VERSION 5.7 ;
  NOWIREEXTENSIONATPIN ON ;
  DIVIDERCHAR "/" ;
  BUSBITCHARS "[]" ;
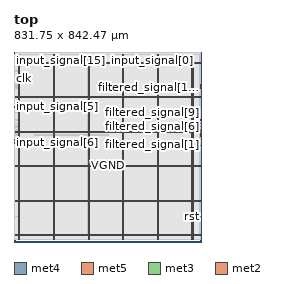
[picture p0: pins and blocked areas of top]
MACRO top
  CLASS BLOCK ;
  FOREIGN top ;
  ORIGIN 0.000 0.000 ;
  SIZE 831.750 BY 842.470 ;
  PIN VGND
    DIRECTION INOUT ;
    USE GROUND ;
    PORT
      LAYER met4 ;
        RECT 24.340 10.640 25.940 829.840 ;
    END
    PORT
      LAYER met4 ;
        RECT 177.940 10.640 179.540 829.840 ;
    END
    PORT
      LAYER met4 ;
        RECT 331.540 10.640 333.140 829.840 ;
    END
    PORT
      LAYER met4 ;
        RECT 485.140 10.640 486.740 829.840 ;
    END
    PORT
      LAYER met4 ;
        RECT 638.740 10.640 640.340 829.840 ;
    END
    PORT
      LAYER met4 ;
        RECT 792.340 10.640 793.940 829.840 ;
    END
    PORT
      LAYER met5 ;
        RECT 5.280 30.030 826.400 31.630 ;
    END
    PORT
      LAYER met5 ;
        RECT 5.280 183.210 826.400 184.810 ;
    END
    PORT
      LAYER met5 ;
        RECT 5.280 336.390 826.400 337.990 ;
    END
    PORT
      LAYER met5 ;
        RECT 5.280 489.570 826.400 491.170 ;
    END
    PORT
      LAYER met5 ;
        RECT 5.280 642.750 826.400 644.350 ;
    END
    PORT
      LAYER met5 ;
        RECT 5.280 795.930 826.400 797.530 ;
    END
  END VGND
  PIN VPWR
    DIRECTION INOUT ;
    USE POWER ;
    PORT
      LAYER met4 ;
        RECT 21.040 10.640 22.640 829.840 ;
    END
    PORT
      LAYER met4 ;
        RECT 174.640 10.640 176.240 829.840 ;
    END
    PORT
      LAYER met4 ;
        RECT 328.240 10.640 329.840 829.840 ;
    END
    PORT
      LAYER met4 ;
        RECT 481.840 10.640 483.440 829.840 ;
    END
    PORT
      LAYER met4 ;
        RECT 635.440 10.640 637.040 829.840 ;
    END
    PORT
      LAYER met4 ;
        RECT 789.040 10.640 790.640 829.840 ;
    END
    PORT
      LAYER met5 ;
        RECT 5.280 26.730 826.400 28.330 ;
    END
    PORT
      LAYER met5 ;
        RECT 5.280 179.910 826.400 181.510 ;
    END
    PORT
      LAYER met5 ;
        RECT 5.280 333.090 826.400 334.690 ;
    END
    PORT
      LAYER met5 ;
        RECT 5.280 486.270 826.400 487.870 ;
    END
    PORT
      LAYER met5 ;
        RECT 5.280 639.450 826.400 641.050 ;
    END
    PORT
      LAYER met5 ;
        RECT 5.280 792.630 826.400 794.230 ;
    END
  END VPWR
  PIN clk
    DIRECTION INPUT ;
    USE SIGNAL ;
    ANTENNAGATEAREA 0.852000 ;
    ANTENNADIFFAREA 0.434700 ;
    PORT
      LAYER met3 ;
        RECT 0.000 758.240 4.000 758.840 ;
    END
  END clk
  PIN filtered_signal[0]
    DIRECTION OUTPUT ;
    USE SIGNAL ;
    ANTENNADIFFAREA 0.445500 ;
    PORT
      LAYER met3 ;
        RECT 827.750 428.440 831.750 429.040 ;
    END
  END filtered_signal[0]
  PIN filtered_signal[10]
    DIRECTION OUTPUT ;
    USE SIGNAL ;
    ANTENNADIFFAREA 0.795200 ;
    PORT
      LAYER met3 ;
        RECT 827.750 697.040 831.750 697.640 ;
    END
  END filtered_signal[10]
  PIN filtered_signal[11]
    DIRECTION OUTPUT ;
    USE SIGNAL ;
    ANTENNADIFFAREA 0.445500 ;
    PORT
      LAYER met3 ;
        RECT 827.750 683.440 831.750 684.040 ;
    END
  END filtered_signal[11]
  PIN filtered_signal[12]
    DIRECTION OUTPUT ;
    USE SIGNAL ;
    ANTENNADIFFAREA 0.795200 ;
    PORT
      LAYER met3 ;
        RECT 827.750 690.240 831.750 690.840 ;
    END
  END filtered_signal[12]
  PIN filtered_signal[13]
    DIRECTION OUTPUT ;
    USE SIGNAL ;
    ANTENNADIFFAREA 0.445500 ;
    PORT
      LAYER met3 ;
        RECT 827.750 686.840 831.750 687.440 ;
    END
  END filtered_signal[13]
  PIN filtered_signal[14]
    DIRECTION OUTPUT ;
    USE SIGNAL ;
    ANTENNADIFFAREA 0.445500 ;
    PORT
      LAYER met3 ;
        RECT 827.750 680.040 831.750 680.640 ;
    END
  END filtered_signal[14]
  PIN filtered_signal[15]
    DIRECTION OUTPUT ;
    USE SIGNAL ;
    ANTENNADIFFAREA 0.795200 ;
    PORT
      LAYER met3 ;
        RECT 827.750 693.640 831.750 694.240 ;
    END
  END filtered_signal[15]
  PIN filtered_signal[1]
    DIRECTION OUTPUT ;
    USE SIGNAL ;
    ANTENNADIFFAREA 0.445500 ;
    PORT
      LAYER met3 ;
        RECT 827.750 469.240 831.750 469.840 ;
    END
  END filtered_signal[1]
  PIN filtered_signal[2]
    DIRECTION OUTPUT ;
    USE SIGNAL ;
    ANTENNADIFFAREA 0.445500 ;
    PORT
      LAYER met3 ;
        RECT 827.750 479.440 831.750 480.040 ;
    END
  END filtered_signal[2]
  PIN filtered_signal[3]
    DIRECTION OUTPUT ;
    USE SIGNAL ;
    ANTENNADIFFAREA 0.445500 ;
    PORT
      LAYER met3 ;
        RECT 827.750 476.040 831.750 476.640 ;
    END
  END filtered_signal[3]
  PIN filtered_signal[4]
    DIRECTION OUTPUT ;
    USE SIGNAL ;
    ANTENNADIFFAREA 0.445500 ;
    PORT
      LAYER met3 ;
        RECT 827.750 499.840 831.750 500.440 ;
    END
  END filtered_signal[4]
  PIN filtered_signal[5]
    DIRECTION OUTPUT ;
    USE SIGNAL ;
    ANTENNADIFFAREA 0.445500 ;
    PORT
      LAYER met3 ;
        RECT 827.750 493.040 831.750 493.640 ;
    END
  END filtered_signal[5]
  PIN filtered_signal[6]
    DIRECTION OUTPUT ;
    USE SIGNAL ;
    ANTENNADIFFAREA 0.445500 ;
    PORT
      LAYER met3 ;
        RECT 827.750 513.440 831.750 514.040 ;
    END
  END filtered_signal[6]
  PIN filtered_signal[7]
    DIRECTION OUTPUT ;
    USE SIGNAL ;
    ANTENNADIFFAREA 0.795200 ;
    PORT
      LAYER met3 ;
        RECT 827.750 510.040 831.750 510.640 ;
    END
  END filtered_signal[7]
  PIN filtered_signal[8]
    DIRECTION OUTPUT ;
    USE SIGNAL ;
    ANTENNADIFFAREA 0.795200 ;
    PORT
      LAYER met3 ;
        RECT 827.750 523.640 831.750 524.240 ;
    END
  END filtered_signal[8]
  PIN filtered_signal[9]
    DIRECTION OUTPUT ;
    USE SIGNAL ;
    ANTENNADIFFAREA 0.445500 ;
    PORT
      LAYER met3 ;
        RECT 827.750 540.640 831.750 541.240 ;
    END
  END filtered_signal[9]
  PIN input_signal[0]
    DIRECTION INPUT ;
    USE SIGNAL ;
    ANTENNAGATEAREA 0.213000 ;
    ANTENNADIFFAREA 0.434700 ;
    PORT
      LAYER met2 ;
        RECT 615.110 838.470 615.390 842.470 ;
    END
  END input_signal[0]
  PIN input_signal[10]
    DIRECTION INPUT ;
    USE SIGNAL ;
    ANTENNAGATEAREA 0.196500 ;
    ANTENNADIFFAREA 0.434700 ;
    PORT
      LAYER met3 ;
        RECT 0.000 455.640 4.000 456.240 ;
    END
  END input_signal[10]
  PIN input_signal[11]
    DIRECTION INPUT ;
    USE SIGNAL ;
    ANTENNAGATEAREA 0.196500 ;
    ANTENNADIFFAREA 0.434700 ;
    PORT
      LAYER met3 ;
        RECT 0.000 448.840 4.000 449.440 ;
    END
  END input_signal[11]
  PIN input_signal[12]
    DIRECTION INPUT ;
    USE SIGNAL ;
    ANTENNAGATEAREA 0.196500 ;
    ANTENNADIFFAREA 0.434700 ;
    PORT
      LAYER met3 ;
        RECT 0.000 428.440 4.000 429.040 ;
    END
  END input_signal[12]
  PIN input_signal[13]
    DIRECTION INPUT ;
    USE SIGNAL ;
    ANTENNAGATEAREA 0.196500 ;
    ANTENNADIFFAREA 0.434700 ;
    PORT
      LAYER met3 ;
        RECT 0.000 431.840 4.000 432.440 ;
    END
  END input_signal[13]
  PIN input_signal[14]
    DIRECTION INPUT ;
    USE SIGNAL ;
    ANTENNAGATEAREA 0.196500 ;
    ANTENNADIFFAREA 0.434700 ;
    PORT
      LAYER met3 ;
        RECT 0.000 452.240 4.000 452.840 ;
    END
  END input_signal[14]
  PIN input_signal[15]
    DIRECTION INPUT ;
    USE SIGNAL ;
    ANTENNAGATEAREA 0.196500 ;
    ANTENNADIFFAREA 0.434700 ;
    PORT
      LAYER met2 ;
        RECT 83.810 838.470 84.090 842.470 ;
    END
  END input_signal[15]
  PIN input_signal[1]
    DIRECTION INPUT ;
    USE SIGNAL ;
    ANTENNAGATEAREA 0.159000 ;
    ANTENNADIFFAREA 0.434700 ;
    PORT
      LAYER met2 ;
        RECT 599.010 838.470 599.290 842.470 ;
    END
  END input_signal[1]
  PIN input_signal[2]
    DIRECTION INPUT ;
    USE SIGNAL ;
    ANTENNAGATEAREA 0.159000 ;
    ANTENNADIFFAREA 0.434700 ;
    PORT
      LAYER met2 ;
        RECT 576.470 838.470 576.750 842.470 ;
    END
  END input_signal[2]
  PIN input_signal[3]
    DIRECTION INPUT ;
    USE SIGNAL ;
    ANTENNAGATEAREA 0.196500 ;
    ANTENNADIFFAREA 0.434700 ;
    PORT
      LAYER met3 ;
        RECT 0.000 574.640 4.000 575.240 ;
    END
  END input_signal[3]
  PIN input_signal[4]
    DIRECTION INPUT ;
    USE SIGNAL ;
    ANTENNAGATEAREA 0.196500 ;
    ANTENNADIFFAREA 0.434700 ;
    PORT
      LAYER met3 ;
        RECT 0.000 595.040 4.000 595.640 ;
    END
  END input_signal[4]
  PIN input_signal[5]
    DIRECTION INPUT ;
    USE SIGNAL ;
    ANTENNAGATEAREA 0.196500 ;
    ANTENNADIFFAREA 0.434700 ;
    PORT
      LAYER met3 ;
        RECT 0.000 598.440 4.000 599.040 ;
    END
  END input_signal[5]
  PIN input_signal[6]
    DIRECTION INPUT ;
    USE SIGNAL ;
    ANTENNAGATEAREA 0.196500 ;
    ANTENNADIFFAREA 0.434700 ;
    PORT
      LAYER met3 ;
        RECT 0.000 442.040 4.000 442.640 ;
    END
  END input_signal[6]
  PIN input_signal[7]
    DIRECTION INPUT ;
    USE SIGNAL ;
    ANTENNAGATEAREA 0.196500 ;
    ANTENNADIFFAREA 0.434700 ;
    PORT
      LAYER met3 ;
        RECT 0.000 435.240 4.000 435.840 ;
    END
  END input_signal[7]
  PIN input_signal[8]
    DIRECTION INPUT ;
    USE SIGNAL ;
    ANTENNAGATEAREA 0.196500 ;
    ANTENNADIFFAREA 0.434700 ;
    PORT
      LAYER met3 ;
        RECT 0.000 445.440 4.000 446.040 ;
    END
  END input_signal[8]
  PIN input_signal[9]
    DIRECTION INPUT ;
    USE SIGNAL ;
    ANTENNAGATEAREA 0.196500 ;
    ANTENNADIFFAREA 0.434700 ;
    PORT
      LAYER met3 ;
        RECT 0.000 438.640 4.000 439.240 ;
    END
  END input_signal[9]
  PIN rst
    DIRECTION INPUT ;
    USE SIGNAL ;
    ANTENNAGATEAREA 0.213000 ;
    ANTENNADIFFAREA 0.434700 ;
    PORT
      LAYER met3 ;
        RECT 827.750 112.240 831.750 112.840 ;
    END
  END rst
  PIN tap[0]
    DIRECTION INPUT ;
    USE SIGNAL ;
    ANTENNAGATEAREA 0.247500 ;
    ANTENNADIFFAREA 0.434700 ;
    PORT
      LAYER met2 ;
        RECT 634.430 838.470 634.710 842.470 ;
    END
  END tap[0]
  PIN tap[1]
    DIRECTION INPUT ;
    USE SIGNAL ;
    ANTENNAGATEAREA 0.213000 ;
    ANTENNADIFFAREA 0.434700 ;
    PORT
      LAYER met2 ;
        RECT 631.210 838.470 631.490 842.470 ;
    END
  END tap[1]
  PIN tap[2]
    DIRECTION INPUT ;
    USE SIGNAL ;
    ANTENNAGATEAREA 0.247500 ;
    ANTENNADIFFAREA 0.434700 ;
    PORT
      LAYER met3 ;
        RECT 827.750 465.840 831.750 466.440 ;
    END
  END tap[2]
  PIN tap[3]
    DIRECTION INPUT ;
    USE SIGNAL ;
    ANTENNAGATEAREA 0.247500 ;
    ANTENNADIFFAREA 0.434700 ;
    PORT
      LAYER met3 ;
        RECT 827.750 472.640 831.750 473.240 ;
    END
  END tap[3]
  OBS
      LAYER li1 ;
        RECT 5.520 10.795 826.160 829.685 ;
      LAYER met1 ;
        RECT 5.130 10.640 827.930 829.840 ;
      LAYER met2 ;
        RECT 5.150 838.190 83.530 838.470 ;
        RECT 84.370 838.190 576.190 838.470 ;
        RECT 577.030 838.190 598.730 838.470 ;
        RECT 599.570 838.190 614.830 838.470 ;
        RECT 615.670 838.190 630.930 838.470 ;
        RECT 631.770 838.190 634.150 838.470 ;
        RECT 634.990 838.190 827.900 838.470 ;
        RECT 5.150 10.695 827.900 838.190 ;
      LAYER met3 ;
        RECT 4.000 759.240 827.750 831.465 ;
        RECT 4.400 757.840 827.750 759.240 ;
        RECT 4.000 698.040 827.750 757.840 ;
        RECT 4.000 696.640 827.350 698.040 ;
        RECT 4.000 694.640 827.750 696.640 ;
        RECT 4.000 693.240 827.350 694.640 ;
        RECT 4.000 691.240 827.750 693.240 ;
        RECT 4.000 689.840 827.350 691.240 ;
        RECT 4.000 687.840 827.750 689.840 ;
        RECT 4.000 686.440 827.350 687.840 ;
        RECT 4.000 684.440 827.750 686.440 ;
        RECT 4.000 683.040 827.350 684.440 ;
        RECT 4.000 681.040 827.750 683.040 ;
        RECT 4.000 679.640 827.350 681.040 ;
        RECT 4.000 599.440 827.750 679.640 ;
        RECT 4.400 598.040 827.750 599.440 ;
        RECT 4.000 596.040 827.750 598.040 ;
        RECT 4.400 594.640 827.750 596.040 ;
        RECT 4.000 575.640 827.750 594.640 ;
        RECT 4.400 574.240 827.750 575.640 ;
        RECT 4.000 541.640 827.750 574.240 ;
        RECT 4.000 540.240 827.350 541.640 ;
        RECT 4.000 524.640 827.750 540.240 ;
        RECT 4.000 523.240 827.350 524.640 ;
        RECT 4.000 514.440 827.750 523.240 ;
        RECT 4.000 513.040 827.350 514.440 ;
        RECT 4.000 511.040 827.750 513.040 ;
        RECT 4.000 509.640 827.350 511.040 ;
        RECT 4.000 500.840 827.750 509.640 ;
        RECT 4.000 499.440 827.350 500.840 ;
        RECT 4.000 494.040 827.750 499.440 ;
        RECT 4.000 492.640 827.350 494.040 ;
        RECT 4.000 480.440 827.750 492.640 ;
        RECT 4.000 479.040 827.350 480.440 ;
        RECT 4.000 477.040 827.750 479.040 ;
        RECT 4.000 475.640 827.350 477.040 ;
        RECT 4.000 473.640 827.750 475.640 ;
        RECT 4.000 472.240 827.350 473.640 ;
        RECT 4.000 470.240 827.750 472.240 ;
        RECT 4.000 468.840 827.350 470.240 ;
        RECT 4.000 466.840 827.750 468.840 ;
        RECT 4.000 465.440 827.350 466.840 ;
        RECT 4.000 456.640 827.750 465.440 ;
        RECT 4.400 455.240 827.750 456.640 ;
        RECT 4.000 453.240 827.750 455.240 ;
        RECT 4.400 451.840 827.750 453.240 ;
        RECT 4.000 449.840 827.750 451.840 ;
        RECT 4.400 448.440 827.750 449.840 ;
        RECT 4.000 446.440 827.750 448.440 ;
        RECT 4.400 445.040 827.750 446.440 ;
        RECT 4.000 443.040 827.750 445.040 ;
        RECT 4.400 441.640 827.750 443.040 ;
        RECT 4.000 439.640 827.750 441.640 ;
        RECT 4.400 438.240 827.750 439.640 ;
        RECT 4.000 436.240 827.750 438.240 ;
        RECT 4.400 434.840 827.750 436.240 ;
        RECT 4.000 432.840 827.750 434.840 ;
        RECT 4.400 431.440 827.750 432.840 ;
        RECT 4.000 429.440 827.750 431.440 ;
        RECT 4.400 428.040 827.350 429.440 ;
        RECT 4.000 113.240 827.750 428.040 ;
        RECT 4.000 111.840 827.350 113.240 ;
        RECT 4.000 10.715 827.750 111.840 ;
      LAYER met4 ;
        RECT 23.295 830.240 820.345 831.465 ;
        RECT 23.295 27.375 23.940 830.240 ;
        RECT 26.340 27.375 174.240 830.240 ;
        RECT 176.640 27.375 177.540 830.240 ;
        RECT 179.940 27.375 327.840 830.240 ;
        RECT 330.240 27.375 331.140 830.240 ;
        RECT 333.540 27.375 481.440 830.240 ;
        RECT 483.840 27.375 484.740 830.240 ;
        RECT 487.140 27.375 635.040 830.240 ;
        RECT 637.440 27.375 638.340 830.240 ;
        RECT 640.740 27.375 788.640 830.240 ;
        RECT 791.040 27.375 791.940 830.240 ;
        RECT 794.340 27.375 820.345 830.240 ;
      LAYER met5 ;
        RECT 91.660 473.500 418.020 475.100 ;
  END
END top
END LIBRARY

